# Generated deterministically by seda-macro-lef-normalizer-v1; recipe orfs-ng45-fakeram-metal3-coupledl2-pg-v1.
VERSION 5.8 ;
BUSBITCHARS "[]" ;
DIVIDERCHAR "/" ;

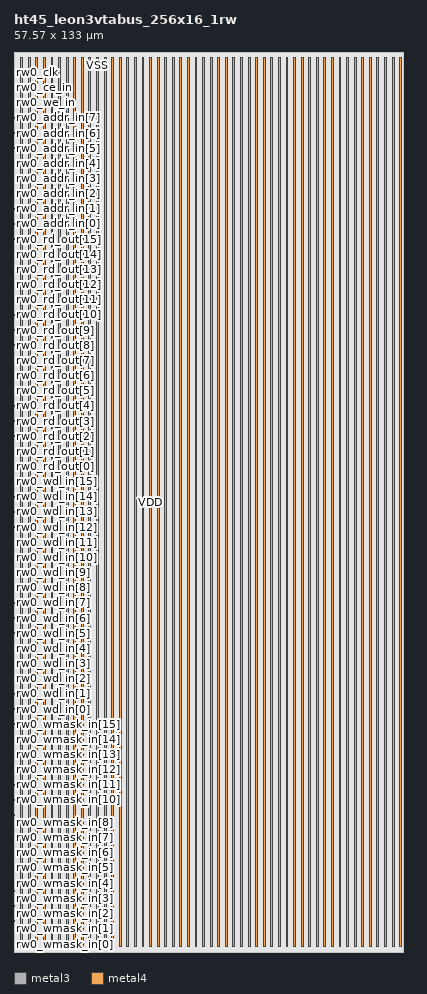
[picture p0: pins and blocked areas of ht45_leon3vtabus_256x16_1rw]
MACRO ht45_leon3vtabus_256x16_1rw
  FOREIGN ht45_leon3vtabus_256x16_1rw 0 0 ;
  CLASS BLOCK ;
  ORIGIN 0 0 ;
  SIZE 57.57 BY 133 ;
  SYMMETRY X Y R90 ;
  PIN rw0_wmask_in[0]
    DIRECTION INPUT ;
    USE SIGNAL ;
    SHAPE ABUTMENT ;
    PORT
      LAYER metal3 ;
      RECT 0 0.035 0.07 0.105 ;
    END
  END rw0_wmask_in[0]
  PIN rw0_wmask_in[1]
    DIRECTION INPUT ;
    USE SIGNAL ;
    SHAPE ABUTMENT ;
    PORT
      LAYER metal3 ;
      RECT 0 2.275 0.07 2.345 ;
    END
  END rw0_wmask_in[1]
  PIN rw0_wmask_in[2]
    DIRECTION INPUT ;
    USE SIGNAL ;
    SHAPE ABUTMENT ;
    PORT
      LAYER metal3 ;
      RECT 0 4.515 0.07 4.585 ;
    END
  END rw0_wmask_in[2]
  PIN rw0_wmask_in[3]
    DIRECTION INPUT ;
    USE SIGNAL ;
    SHAPE ABUTMENT ;
    PORT
      LAYER metal3 ;
      RECT 0 6.755 0.07 6.825 ;
    END
  END rw0_wmask_in[3]
  PIN rw0_wmask_in[4]
    DIRECTION INPUT ;
    USE SIGNAL ;
    SHAPE ABUTMENT ;
    PORT
      LAYER metal3 ;
      RECT 0 8.995 0.07 9.065 ;
    END
  END rw0_wmask_in[4]
  PIN rw0_wmask_in[5]
    DIRECTION INPUT ;
    USE SIGNAL ;
    SHAPE ABUTMENT ;
    PORT
      LAYER metal3 ;
      RECT 0 11.235 0.07 11.305 ;
    END
  END rw0_wmask_in[5]
  PIN rw0_wmask_in[6]
    DIRECTION INPUT ;
    USE SIGNAL ;
    SHAPE ABUTMENT ;
    PORT
      LAYER metal3 ;
      RECT 0 13.475 0.07 13.545 ;
    END
  END rw0_wmask_in[6]
  PIN rw0_wmask_in[7]
    DIRECTION INPUT ;
    USE SIGNAL ;
    SHAPE ABUTMENT ;
    PORT
      LAYER metal3 ;
      RECT 0 15.715 0.07 15.785 ;
    END
  END rw0_wmask_in[7]
  PIN rw0_wmask_in[8]
    DIRECTION INPUT ;
    USE SIGNAL ;
    SHAPE ABUTMENT ;
    PORT
      LAYER metal3 ;
      RECT 0 17.955 0.07 18.025 ;
    END
  END rw0_wmask_in[8]
  PIN rw0_wmask_in[9]
    DIRECTION INPUT ;
    USE SIGNAL ;
    SHAPE ABUTMENT ;
    PORT
      LAYER metal3 ;
      RECT 0 20.195 0.07 20.265 ;
    END
  END rw0_wmask_in[9]
  PIN rw0_wmask_in[10]
    DIRECTION INPUT ;
    USE SIGNAL ;
    SHAPE ABUTMENT ;
    PORT
      LAYER metal3 ;
      RECT 0 22.435 0.07 22.505 ;
    END
  END rw0_wmask_in[10]
  PIN rw0_wmask_in[11]
    DIRECTION INPUT ;
    USE SIGNAL ;
    SHAPE ABUTMENT ;
    PORT
      LAYER metal3 ;
      RECT 0 24.675 0.07 24.745 ;
    END
  END rw0_wmask_in[11]
  PIN rw0_wmask_in[12]
    DIRECTION INPUT ;
    USE SIGNAL ;
    SHAPE ABUTMENT ;
    PORT
      LAYER metal3 ;
      RECT 0 26.915 0.07 26.985 ;
    END
  END rw0_wmask_in[12]
  PIN rw0_wmask_in[13]
    DIRECTION INPUT ;
    USE SIGNAL ;
    SHAPE ABUTMENT ;
    PORT
      LAYER metal3 ;
      RECT 0 29.155 0.07 29.225 ;
    END
  END rw0_wmask_in[13]
  PIN rw0_wmask_in[14]
    DIRECTION INPUT ;
    USE SIGNAL ;
    SHAPE ABUTMENT ;
    PORT
      LAYER metal3 ;
      RECT 0 31.395 0.07 31.465 ;
    END
  END rw0_wmask_in[14]
  PIN rw0_wmask_in[15]
    DIRECTION INPUT ;
    USE SIGNAL ;
    SHAPE ABUTMENT ;
    PORT
      LAYER metal3 ;
      RECT 0 33.635 0.07 33.705 ;
    END
  END rw0_wmask_in[15]
  PIN rw0_wd_in[0]
    DIRECTION INPUT ;
    USE SIGNAL ;
    SHAPE ABUTMENT ;
    PORT
      LAYER metal3 ;
      RECT 0 35.875 0.07 35.945 ;
    END
  END rw0_wd_in[0]
  PIN rw0_wd_in[1]
    DIRECTION INPUT ;
    USE SIGNAL ;
    SHAPE ABUTMENT ;
    PORT
      LAYER metal3 ;
      RECT 0 38.115 0.07 38.185 ;
    END
  END rw0_wd_in[1]
  PIN rw0_wd_in[2]
    DIRECTION INPUT ;
    USE SIGNAL ;
    SHAPE ABUTMENT ;
    PORT
      LAYER metal3 ;
      RECT 0 40.355 0.07 40.425 ;
    END
  END rw0_wd_in[2]
  PIN rw0_wd_in[3]
    DIRECTION INPUT ;
    USE SIGNAL ;
    SHAPE ABUTMENT ;
    PORT
      LAYER metal3 ;
      RECT 0 42.595 0.07 42.665 ;
    END
  END rw0_wd_in[3]
  PIN rw0_wd_in[4]
    DIRECTION INPUT ;
    USE SIGNAL ;
    SHAPE ABUTMENT ;
    PORT
      LAYER metal3 ;
      RECT 0 44.835 0.07 44.905 ;
    END
  END rw0_wd_in[4]
  PIN rw0_wd_in[5]
    DIRECTION INPUT ;
    USE SIGNAL ;
    SHAPE ABUTMENT ;
    PORT
      LAYER metal3 ;
      RECT 0 47.075 0.07 47.145 ;
    END
  END rw0_wd_in[5]
  PIN rw0_wd_in[6]
    DIRECTION INPUT ;
    USE SIGNAL ;
    SHAPE ABUTMENT ;
    PORT
      LAYER metal3 ;
      RECT 0 49.315 0.07 49.385 ;
    END
  END rw0_wd_in[6]
  PIN rw0_wd_in[7]
    DIRECTION INPUT ;
    USE SIGNAL ;
    SHAPE ABUTMENT ;
    PORT
      LAYER metal3 ;
      RECT 0 51.555 0.07 51.625 ;
    END
  END rw0_wd_in[7]
  PIN rw0_wd_in[8]
    DIRECTION INPUT ;
    USE SIGNAL ;
    SHAPE ABUTMENT ;
    PORT
      LAYER metal3 ;
      RECT 0 53.795 0.07 53.865 ;
    END
  END rw0_wd_in[8]
  PIN rw0_wd_in[9]
    DIRECTION INPUT ;
    USE SIGNAL ;
    SHAPE ABUTMENT ;
    PORT
      LAYER metal3 ;
      RECT 0 56.035 0.07 56.105 ;
    END
  END rw0_wd_in[9]
  PIN rw0_wd_in[10]
    DIRECTION INPUT ;
    USE SIGNAL ;
    SHAPE ABUTMENT ;
    PORT
      LAYER metal3 ;
      RECT 0 58.275 0.07 58.345 ;
    END
  END rw0_wd_in[10]
  PIN rw0_wd_in[11]
    DIRECTION INPUT ;
    USE SIGNAL ;
    SHAPE ABUTMENT ;
    PORT
      LAYER metal3 ;
      RECT 0 60.515 0.07 60.585 ;
    END
  END rw0_wd_in[11]
  PIN rw0_wd_in[12]
    DIRECTION INPUT ;
    USE SIGNAL ;
    SHAPE ABUTMENT ;
    PORT
      LAYER metal3 ;
      RECT 0 62.755 0.07 62.825 ;
    END
  END rw0_wd_in[12]
  PIN rw0_wd_in[13]
    DIRECTION INPUT ;
    USE SIGNAL ;
    SHAPE ABUTMENT ;
    PORT
      LAYER metal3 ;
      RECT 0 64.995 0.07 65.065 ;
    END
  END rw0_wd_in[13]
  PIN rw0_wd_in[14]
    DIRECTION INPUT ;
    USE SIGNAL ;
    SHAPE ABUTMENT ;
    PORT
      LAYER metal3 ;
      RECT 0 67.235 0.07 67.305 ;
    END
  END rw0_wd_in[14]
  PIN rw0_wd_in[15]
    DIRECTION INPUT ;
    USE SIGNAL ;
    SHAPE ABUTMENT ;
    PORT
      LAYER metal3 ;
      RECT 0 69.475 0.07 69.545 ;
    END
  END rw0_wd_in[15]
  PIN rw0_rd_out[0]
    DIRECTION OUTPUT ;
    USE SIGNAL ;
    SHAPE ABUTMENT ;
    PORT
      LAYER metal3 ;
      RECT 0 71.715 0.07 71.785 ;
    END
  END rw0_rd_out[0]
  PIN rw0_rd_out[1]
    DIRECTION OUTPUT ;
    USE SIGNAL ;
    SHAPE ABUTMENT ;
    PORT
      LAYER metal3 ;
      RECT 0 73.955 0.07 74.025 ;
    END
  END rw0_rd_out[1]
  PIN rw0_rd_out[2]
    DIRECTION OUTPUT ;
    USE SIGNAL ;
    SHAPE ABUTMENT ;
    PORT
      LAYER metal3 ;
      RECT 0 76.195 0.07 76.265 ;
    END
  END rw0_rd_out[2]
  PIN rw0_rd_out[3]
    DIRECTION OUTPUT ;
    USE SIGNAL ;
    SHAPE ABUTMENT ;
    PORT
      LAYER metal3 ;
      RECT 0 78.435 0.07 78.505 ;
    END
  END rw0_rd_out[3]
  PIN rw0_rd_out[4]
    DIRECTION OUTPUT ;
    USE SIGNAL ;
    SHAPE ABUTMENT ;
    PORT
      LAYER metal3 ;
      RECT 0 80.675 0.07 80.745 ;
    END
  END rw0_rd_out[4]
  PIN rw0_rd_out[5]
    DIRECTION OUTPUT ;
    USE SIGNAL ;
    SHAPE ABUTMENT ;
    PORT
      LAYER metal3 ;
      RECT 0 82.915 0.07 82.985 ;
    END
  END rw0_rd_out[5]
  PIN rw0_rd_out[6]
    DIRECTION OUTPUT ;
    USE SIGNAL ;
    SHAPE ABUTMENT ;
    PORT
      LAYER metal3 ;
      RECT 0 85.155 0.07 85.225 ;
    END
  END rw0_rd_out[6]
  PIN rw0_rd_out[7]
    DIRECTION OUTPUT ;
    USE SIGNAL ;
    SHAPE ABUTMENT ;
    PORT
      LAYER metal3 ;
      RECT 0 87.395 0.07 87.465 ;
    END
  END rw0_rd_out[7]
  PIN rw0_rd_out[8]
    DIRECTION OUTPUT ;
    USE SIGNAL ;
    SHAPE ABUTMENT ;
    PORT
      LAYER metal3 ;
      RECT 0 89.635 0.07 89.705 ;
    END
  END rw0_rd_out[8]
  PIN rw0_rd_out[9]
    DIRECTION OUTPUT ;
    USE SIGNAL ;
    SHAPE ABUTMENT ;
    PORT
      LAYER metal3 ;
      RECT 0 91.875 0.07 91.945 ;
    END
  END rw0_rd_out[9]
  PIN rw0_rd_out[10]
    DIRECTION OUTPUT ;
    USE SIGNAL ;
    SHAPE ABUTMENT ;
    PORT
      LAYER metal3 ;
      RECT 0 94.115 0.07 94.185 ;
    END
  END rw0_rd_out[10]
  PIN rw0_rd_out[11]
    DIRECTION OUTPUT ;
    USE SIGNAL ;
    SHAPE ABUTMENT ;
    PORT
      LAYER metal3 ;
      RECT 0 96.355 0.07 96.425 ;
    END
  END rw0_rd_out[11]
  PIN rw0_rd_out[12]
    DIRECTION OUTPUT ;
    USE SIGNAL ;
    SHAPE ABUTMENT ;
    PORT
      LAYER metal3 ;
      RECT 0 98.595 0.07 98.665 ;
    END
  END rw0_rd_out[12]
  PIN rw0_rd_out[13]
    DIRECTION OUTPUT ;
    USE SIGNAL ;
    SHAPE ABUTMENT ;
    PORT
      LAYER metal3 ;
      RECT 0 100.835 0.07 100.905 ;
    END
  END rw0_rd_out[13]
  PIN rw0_rd_out[14]
    DIRECTION OUTPUT ;
    USE SIGNAL ;
    SHAPE ABUTMENT ;
    PORT
      LAYER metal3 ;
      RECT 0 103.075 0.07 103.145 ;
    END
  END rw0_rd_out[14]
  PIN rw0_rd_out[15]
    DIRECTION OUTPUT ;
    USE SIGNAL ;
    SHAPE ABUTMENT ;
    PORT
      LAYER metal3 ;
      RECT 0 105.315 0.07 105.385 ;
    END
  END rw0_rd_out[15]
  PIN rw0_addr_in[0]
    DIRECTION INPUT ;
    USE SIGNAL ;
    SHAPE ABUTMENT ;
    PORT
      LAYER metal3 ;
      RECT 0 107.555 0.07 107.625 ;
    END
  END rw0_addr_in[0]
  PIN rw0_addr_in[1]
    DIRECTION INPUT ;
    USE SIGNAL ;
    SHAPE ABUTMENT ;
    PORT
      LAYER metal3 ;
      RECT 0 109.795 0.07 109.865 ;
    END
  END rw0_addr_in[1]
  PIN rw0_addr_in[2]
    DIRECTION INPUT ;
    USE SIGNAL ;
    SHAPE ABUTMENT ;
    PORT
      LAYER metal3 ;
      RECT 0 112.035 0.07 112.105 ;
    END
  END rw0_addr_in[2]
  PIN rw0_addr_in[3]
    DIRECTION INPUT ;
    USE SIGNAL ;
    SHAPE ABUTMENT ;
    PORT
      LAYER metal3 ;
      RECT 0 114.275 0.07 114.345 ;
    END
  END rw0_addr_in[3]
  PIN rw0_addr_in[4]
    DIRECTION INPUT ;
    USE SIGNAL ;
    SHAPE ABUTMENT ;
    PORT
      LAYER metal3 ;
      RECT 0 116.515 0.07 116.585 ;
    END
  END rw0_addr_in[4]
  PIN rw0_addr_in[5]
    DIRECTION INPUT ;
    USE SIGNAL ;
    SHAPE ABUTMENT ;
    PORT
      LAYER metal3 ;
      RECT 0 118.755 0.07 118.825 ;
    END
  END rw0_addr_in[5]
  PIN rw0_addr_in[6]
    DIRECTION INPUT ;
    USE SIGNAL ;
    SHAPE ABUTMENT ;
    PORT
      LAYER metal3 ;
      RECT 0 120.995 0.07 121.065 ;
    END
  END rw0_addr_in[6]
  PIN rw0_addr_in[7]
    DIRECTION INPUT ;
    USE SIGNAL ;
    SHAPE ABUTMENT ;
    PORT
      LAYER metal3 ;
      RECT 0 123.235 0.07 123.305 ;
    END
  END rw0_addr_in[7]
  PIN rw0_we_in
    DIRECTION INPUT ;
    USE SIGNAL ;
    SHAPE ABUTMENT ;
    PORT
      LAYER metal3 ;
      RECT 0 125.475 0.07 125.545 ;
    END
  END rw0_we_in
  PIN rw0_ce_in
    DIRECTION INPUT ;
    USE SIGNAL ;
    SHAPE ABUTMENT ;
    PORT
      LAYER metal3 ;
      RECT 0 127.715 0.07 127.785 ;
    END
  END rw0_ce_in
  PIN rw0_clk
    DIRECTION INPUT ;
    USE SIGNAL ;
    SHAPE ABUTMENT ;
    PORT
      LAYER metal3 ;
      RECT 0 129.955 0.07 130.025 ;
    END
  END rw0_clk
  PIN VSS
    DIRECTION INOUT ;
    USE GROUND ;
    PORT
      LAYER metal4 ;
      RECT 1 0.84 1.28 132.16 ;
      RECT 3.24 0.84 3.52 132.16 ;
      RECT 5.48 0.84 5.76 132.16 ;
      RECT 7.72 0.84 8 132.16 ;
      RECT 9.96 0.84 10.24 132.16 ;
      RECT 12.2 0.84 12.48 132.16 ;
      RECT 14.44 0.84 14.72 132.16 ;
      RECT 16.68 0.84 16.96 132.16 ;
      RECT 18.92 0.84 19.2 132.16 ;
      RECT 21.16 0.84 21.44 132.16 ;
      RECT 23.4 0.84 23.68 132.16 ;
      RECT 25.64 0.84 25.92 132.16 ;
      RECT 27.88 0.84 28.16 132.16 ;
      RECT 30.12 0.84 30.4 132.16 ;
      RECT 32.36 0.84 32.64 132.16 ;
      RECT 34.6 0.84 34.88 132.16 ;
      RECT 36.84 0.84 37.12 132.16 ;
      RECT 39.08 0.84 39.36 132.16 ;
      RECT 41.32 0.84 41.6 132.16 ;
      RECT 43.56 0.84 43.84 132.16 ;
      RECT 45.8 0.84 46.08 132.16 ;
      RECT 48.04 0.84 48.32 132.16 ;
      RECT 50.28 0.84 50.56 132.16 ;
      RECT 52.52 0.84 52.8 132.16 ;
      RECT 54.76 0.84 55.04 132.16 ;
      RECT 57 0.84 57.28 132.16 ;
    END
  END VSS
  PIN VDD
    DIRECTION INOUT ;
    USE POWER ;
    PORT
      LAYER metal4 ;
      RECT 2.12 0.84 2.4 132.16 ;
      RECT 4.36 0.84 4.64 132.16 ;
      RECT 6.6 0.84 6.88 132.16 ;
      RECT 8.84 0.84 9.12 132.16 ;
      RECT 11.08 0.84 11.36 132.16 ;
      RECT 13.32 0.84 13.6 132.16 ;
      RECT 15.56 0.84 15.84 132.16 ;
      RECT 17.8 0.84 18.08 132.16 ;
      RECT 20.04 0.84 20.32 132.16 ;
      RECT 22.28 0.84 22.56 132.16 ;
      RECT 24.52 0.84 24.8 132.16 ;
      RECT 26.76 0.84 27.04 132.16 ;
      RECT 29 0.84 29.28 132.16 ;
      RECT 31.24 0.84 31.52 132.16 ;
      RECT 33.48 0.84 33.76 132.16 ;
      RECT 35.72 0.84 36 132.16 ;
      RECT 37.96 0.84 38.24 132.16 ;
      RECT 40.2 0.84 40.48 132.16 ;
      RECT 42.44 0.84 42.72 132.16 ;
      RECT 44.68 0.84 44.96 132.16 ;
      RECT 46.92 0.84 47.2 132.16 ;
      RECT 49.16 0.84 49.44 132.16 ;
      RECT 51.4 0.84 51.68 132.16 ;
      RECT 53.64 0.84 53.92 132.16 ;
      RECT 55.88 0.84 56.16 132.16 ;
    END
  END VDD
  OBS
    LAYER metal1 ;
    RECT 0 0 57.57 133 ;
    LAYER metal2 ;
    RECT 0 0 57.57 133 ;
  END
END ht45_leon3vtabus_256x16_1rw

END LIBRARY
